VERSION 5.8 ;
BUSBITCHARS "[]" ;
DIVIDERCHAR "/" ;
UNITS
    DATABASE MICRONS 1000 ;
END UNITS

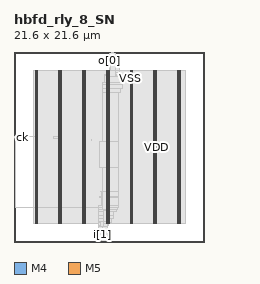
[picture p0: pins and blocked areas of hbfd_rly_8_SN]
MACRO hbfd_rly_8_SN
  FOREIGN hbfd_rly_8_SN 0 0 ;
  CLASS BLOCK ;
  SIZE 21.6 BY 21.6 ;
  PIN ck
    DIRECTION INPUT ;
    USE SIGNAL ;
    PORT
      LAYER M4 ;
        RECT  0 11.856 0.084 11.88 ;
    END
  END ck
  PIN i[0]
    DIRECTION INPUT ;
    USE SIGNAL ;
    PORT
      LAYER M5 ;
        RECT  9.936 0 9.96 0.084 ;
    END
  END i[0]
  PIN i[1]
    DIRECTION INPUT ;
    USE SIGNAL ;
    PORT
      LAYER M5 ;
        RECT  10.032 0 10.056 0.084 ;
    END
  END i[1]
  PIN i[2]
    DIRECTION INPUT ;
    USE SIGNAL ;
    PORT
      LAYER M5 ;
        RECT  10.128 0 10.152 0.084 ;
    END
  END i[2]
  PIN i[3]
    DIRECTION INPUT ;
    USE SIGNAL ;
    PORT
      LAYER M5 ;
        RECT  10.224 0 10.248 0.084 ;
    END
  END i[3]
  PIN i[4]
    DIRECTION INPUT ;
    USE SIGNAL ;
    PORT
      LAYER M5 ;
        RECT  10.32 0 10.344 0.084 ;
    END
  END i[4]
  PIN i[5]
    DIRECTION INPUT ;
    USE SIGNAL ;
    PORT
      LAYER M5 ;
        RECT  10.416 0 10.44 0.084 ;
    END
  END i[5]
  PIN i[6]
    DIRECTION INPUT ;
    USE SIGNAL ;
    PORT
      LAYER M5 ;
        RECT  10.512 0 10.536 0.084 ;
    END
  END i[6]
  PIN i[7]
    DIRECTION INPUT ;
    USE SIGNAL ;
    PORT
      LAYER M5 ;
        RECT  10.608 0 10.632 0.084 ;
    END
  END i[7]
  PIN o[0]
    DIRECTION OUTPUT ;
    USE SIGNAL ;
    PORT
      LAYER M5 ;
        RECT  10.896 21.516 10.92 21.6 ;
    END
  END o[0]
  PIN o[1]
    DIRECTION OUTPUT ;
    USE SIGNAL ;
    PORT
      LAYER M5 ;
        RECT  10.992 21.516 11.016 21.6 ;
    END
  END o[1]
  PIN o[2]
    DIRECTION OUTPUT ;
    USE SIGNAL ;
    PORT
      LAYER M5 ;
        RECT  11.088 21.516 11.112 21.6 ;
    END
  END o[2]
  PIN o[3]
    DIRECTION OUTPUT ;
    USE SIGNAL ;
    PORT
      LAYER M5 ;
        RECT  11.184 21.516 11.208 21.6 ;
    END
  END o[3]
  PIN o[4]
    DIRECTION OUTPUT ;
    USE SIGNAL ;
    PORT
      LAYER M5 ;
        RECT  11.28 21.516 11.304 21.6 ;
    END
  END o[4]
  PIN o[5]
    DIRECTION OUTPUT ;
    USE SIGNAL ;
    PORT
      LAYER M5 ;
        RECT  11.376 21.516 11.4 21.6 ;
    END
  END o[5]
  PIN o[6]
    DIRECTION OUTPUT ;
    USE SIGNAL ;
    PORT
      LAYER M5 ;
        RECT  11.472 21.516 11.496 21.6 ;
    END
  END o[6]
  PIN o[7]
    DIRECTION OUTPUT ;
    USE SIGNAL ;
    PORT
      LAYER M5 ;
        RECT  11.568 21.516 11.592 21.6 ;
    END
  END o[7]
  PIN rs
    DIRECTION INPUT ;
    USE SIGNAL ;
    PORT
      LAYER M4 ;
        RECT  0 11.952 0.084 11.976 ;
    END
  END rs
  PIN VDD
    DIRECTION INOUT ;
    USE POWER ;
    PORT
      LAYER M5 ;
        RECT  18.792 2.151 18.912 19.449 ;
        RECT  16.092 2.151 16.212 19.449 ;
        RECT  13.392 2.151 13.512 19.449 ;
        RECT  10.692 2.151 10.812 19.449 ;
        RECT  7.992 2.151 8.112 19.449 ;
        RECT  5.292 2.151 5.412 19.449 ;
        RECT  2.592 2.151 2.712 19.449 ;
    END
  END VDD
  PIN VSS
    DIRECTION INOUT ;
    USE GROUND ;
    PORT
      LAYER M5 ;
        RECT  18.6 2.137 18.72 19.463 ;
        RECT  15.9 2.137 16.02 19.463 ;
        RECT  13.2 2.137 13.32 19.463 ;
        RECT  10.5 2.137 10.62 19.463 ;
        RECT  7.8 2.137 7.92 19.463 ;
        RECT  5.1 2.137 5.22 19.463 ;
        RECT  2.4 2.137 2.52 19.463 ;
    END
  END VSS
  # OT_OBS_CLOSED layer=M5 d_um=1.536 added=3
  OBS
    LAYER RVTN ;
     RECT  2.16 2.16 19.44 2.295 ;
     RECT  2.16 2.565 19.44 2.835 ;
     RECT  2.16 3.105 19.44 3.375 ;
     RECT  2.16 3.645 19.44 3.915 ;
     RECT  2.16 4.185 19.44 4.455 ;
     RECT  2.16 4.725 19.44 4.995 ;
     RECT  2.16 5.265 19.44 5.535 ;
     RECT  2.16 5.805 19.44 6.075 ;
     RECT  2.16 6.345 19.44 6.615 ;
     RECT  2.16 6.885 19.44 7.155 ;
     RECT  2.16 7.425 19.44 7.695 ;
     RECT  2.16 7.965 19.44 8.235 ;
     RECT  2.16 8.505 19.44 8.775 ;
     RECT  2.16 9.045 19.44 9.315 ;
     RECT  2.16 9.585 19.44 9.855 ;
     RECT  2.16 10.125 19.44 10.395 ;
     RECT  2.16 10.665 19.44 10.935 ;
     RECT  2.16 11.205 19.44 11.475 ;
     RECT  2.16 11.745 19.44 12.015 ;
     RECT  2.16 12.285 19.44 12.555 ;
     RECT  2.16 12.825 19.44 13.095 ;
     RECT  2.16 13.365 19.44 13.635 ;
     RECT  2.16 13.905 19.44 14.175 ;
     RECT  2.16 14.445 19.44 14.715 ;
     RECT  2.16 14.985 19.44 15.255 ;
     RECT  2.16 15.525 19.44 15.795 ;
     RECT  2.16 16.065 19.44 16.335 ;
     RECT  2.16 16.605 19.44 16.875 ;
     RECT  2.16 17.145 19.44 17.415 ;
     RECT  2.16 17.685 19.44 17.955 ;
     RECT  2.16 18.225 19.44 18.495 ;
     RECT  2.16 18.765 19.44 19.035 ;
     RECT  2.16 19.305 19.44 19.44 ;
    LAYER RVTP ;
     RECT  2.16 2.295 19.44 2.565 ;
     RECT  2.16 2.835 19.44 3.105 ;
     RECT  2.16 3.375 19.44 3.645 ;
     RECT  2.16 3.915 19.44 4.185 ;
     RECT  2.16 4.455 19.44 4.725 ;
     RECT  2.16 4.995 19.44 5.265 ;
     RECT  2.16 5.535 19.44 5.805 ;
     RECT  2.16 6.075 19.44 6.345 ;
     RECT  2.16 6.615 19.44 6.885 ;
     RECT  2.16 7.155 19.44 7.425 ;
     RECT  2.16 7.695 19.44 7.965 ;
     RECT  2.16 8.235 19.44 8.505 ;
     RECT  2.16 8.775 19.44 9.045 ;
     RECT  2.16 9.315 19.44 9.585 ;
     RECT  2.16 9.855 19.44 10.125 ;
     RECT  2.16 10.395 19.44 10.665 ;
     RECT  2.16 10.935 19.44 11.205 ;
     RECT  2.16 11.475 19.44 11.745 ;
     RECT  2.16 12.015 19.44 12.285 ;
     RECT  2.16 12.555 19.44 12.825 ;
     RECT  2.16 13.095 19.44 13.365 ;
     RECT  2.16 13.635 19.44 13.905 ;
     RECT  2.16 14.175 19.44 14.445 ;
     RECT  2.16 14.715 19.44 14.985 ;
     RECT  2.16 15.255 19.44 15.525 ;
     RECT  2.16 15.795 19.44 16.065 ;
     RECT  2.16 16.335 19.44 16.605 ;
     RECT  2.16 16.875 19.44 17.145 ;
     RECT  2.16 17.415 19.44 17.685 ;
     RECT  2.16 17.955 19.44 18.225 ;
     RECT  2.16 18.495 19.44 18.765 ;
     RECT  2.16 19.035 19.44 19.305 ;
    LAYER M1 ;
     RECT  2.16 2.151 19.44 19.449 ;
    LAYER M2 ;
     RECT  2.16 2.151 19.44 19.449 ;
    LAYER M3 ;
     RECT  10.188 0.091 10.206 0.571 ;
     RECT  9.576 0.571 10.206 1.723 ;
     RECT  9.576 1.723 10.674 1.819 ;
     RECT  9.576 1.819 10.71 2.191 ;
     RECT  2.415 2.143 2.505 2.413 ;
     RECT  5.115 2.143 5.205 2.413 ;
     RECT  7.815 2.143 7.905 2.413 ;
     RECT  13.215 2.143 13.305 2.413 ;
     RECT  15.915 2.143 16.005 2.413 ;
     RECT  18.615 2.143 18.705 2.413 ;
     RECT  9.576 2.191 11.106 2.641 ;
     RECT  9.576 2.641 11.358 3.065 ;
     RECT  9.612 3.065 11.358 3.451 ;
     RECT  9.612 3.451 11.682 3.721 ;
     RECT  9.612 3.721 11.718 3.953 ;
     RECT  9.612 3.953 11.826 4.145 ;
     RECT  9.972 4.145 11.826 5.035 ;
     RECT  9.684 5.035 11.826 5.071 ;
     RECT  9.684 5.071 11.898 5.225 ;
     RECT  9.9 5.225 11.898 5.765 ;
     RECT  10.008 5.765 11.898 8.509 ;
     RECT  9.684 8.509 11.898 11.399 ;
     RECT  8.82 11.515 8.838 11.669 ;
     RECT  5.115 2.413 5.397 11.785 ;
     RECT  4.464 11.785 5.397 11.939 ;
     RECT  2.415 2.413 2.697 11.941 ;
     RECT  2.304 11.941 2.697 11.981 ;
     RECT  10.044 11.399 11.898 17.041 ;
     RECT  10.044 17.041 12.114 17.491 ;
     RECT  10.044 17.491 12.294 17.915 ;
     RECT  10.044 17.915 12.222 18.149 ;
     RECT  10.26 18.149 12.222 18.959 ;
     RECT  10.26 18.959 12.114 18.995 ;
     RECT  2.415 11.981 2.697 19.187 ;
     RECT  5.115 11.939 5.397 19.187 ;
     RECT  7.815 2.413 8.097 19.187 ;
     RECT  13.215 2.413 13.497 19.187 ;
     RECT  15.915 2.413 16.197 19.187 ;
     RECT  18.615 2.413 18.897 19.187 ;
     RECT  10.515 18.995 12.114 19.229 ;
     RECT  10.515 19.229 12.042 19.265 ;
     RECT  2.415 19.187 2.505 19.457 ;
     RECT  5.115 19.187 5.205 19.457 ;
     RECT  7.815 19.187 7.905 19.457 ;
     RECT  10.515 19.265 11.97 19.457 ;
     RECT  13.215 19.187 13.305 19.457 ;
     RECT  15.915 19.187 16.005 19.457 ;
     RECT  18.615 19.187 18.705 19.457 ;
     RECT  10.872 19.457 11.97 19.949 ;
     RECT  10.872 19.949 11.178 19.997 ;
     RECT  11.16 19.997 11.178 20.525 ;
     RECT  11.952 19.949 11.97 20.525 ;
    LAYER M4 ;
     RECT  0.06 11.856 0.227 11.976 ;
     RECT  0.181 3.888 2.408 3.912 ;
     RECT  0.227 11.952 2.408 11.976 ;
     RECT  2.408 2.148 2.512 19.452 ;
     RECT  2.512 2.418 2.704 19.182 ;
     RECT  2.704 3.888 5.108 3.912 ;
     RECT  5.108 2.148 5.212 19.452 ;
     RECT  5.212 2.418 5.404 19.182 ;
     RECT  5.404 3.888 7.808 3.912 ;
     RECT  7.808 2.148 7.912 19.452 ;
     RECT  7.912 2.418 8.104 19.182 ;
     RECT  9.601 2.256 9.853 2.28 ;
     RECT  9.565 0.576 9.971 0.6 ;
     RECT  8.104 3.888 10.028 3.912 ;
     RECT  10.028 3.696 10.316 3.912 ;
     RECT  10.316 3.6 10.357 3.912 ;
     RECT  10.177 0.096 10.451 0.12 ;
     RECT  9.853 1.728 10.508 2.28 ;
     RECT  10.357 3.6 10.508 3.96 ;
     RECT  9.889 5.712 10.508 5.736 ;
     RECT  10.508 1.728 10.685 19.452 ;
     RECT  10.685 1.824 10.721 19.452 ;
     RECT  10.721 2.418 10.804 19.452 ;
     RECT  10.804 18.816 10.861 19.452 ;
     RECT  10.861 18.816 10.885 19.992 ;
     RECT  10.885 18.816 11.297 20.52 ;
     RECT  11.297 18.816 11.411 19.368 ;
     RECT  11.411 18.816 11.981 18.84 ;
     RECT  11.297 20.496 11.981 20.52 ;
     RECT  13.208 2.148 13.312 19.452 ;
     RECT  13.312 2.418 13.504 19.182 ;
     RECT  15.908 2.148 16.012 19.452 ;
     RECT  16.012 2.418 16.204 19.182 ;
     RECT  18.608 2.148 18.712 19.452 ;
     RECT  18.712 2.418 18.904 19.182 ;
    LAYER M5 ;
     RECT  9.936 0.016 10.632 0.611 ;
     RECT  10.032 0.611 10.632 1.763 ;
     RECT  2.4 2.137 2.52 2.151 ;
     RECT  5.1 2.137 5.22 2.151 ;
     RECT  7.8 2.137 7.92 2.151 ;
     RECT  10.128 1.763 10.632 2.151 ;
     RECT  13.2 2.137 13.32 2.151 ;
     RECT  15.9 2.137 16.02 2.151 ;
     RECT  18.6 2.137 18.72 2.151 ;
     RECT  10.128 2.151 10.812 2.291 ;
     RECT  10.5 2.291 10.812 3.589 ;
     RECT  10.368 3.589 10.812 3.685 ;
     RECT  10.08 3.685 10.812 5.747 ;
     RECT  0.192 3.877 0.216 11.891 ;
     RECT  10.5 5.747 10.812 18.805 ;
     RECT  2.4 2.151 2.712 19.449 ;
     RECT  5.1 2.151 5.412 19.449 ;
     RECT  7.8 2.151 8.112 19.449 ;
     RECT  13.2 2.151 13.512 19.449 ;
     RECT  15.9 2.151 16.212 19.449 ;
     RECT  18.6 2.151 18.912 19.449 ;
     RECT  2.4 19.449 2.52 19.463 ;
     RECT  5.1 19.449 5.22 19.463 ;
     RECT  7.8 19.449 7.92 19.463 ;
     RECT  10.5 18.805 11.496 19.463 ;
     RECT  13.2 19.449 13.32 19.463 ;
     RECT  15.9 19.449 16.02 19.463 ;
     RECT  18.6 19.449 18.72 19.463 ;
     RECT  10.992 19.463 11.496 20.485 ;
     RECT  10.896 20.485 11.592 21.584 ;
     RECT  10.128 2.291 10.5 3.589 ;
     RECT  10.128 3.589 10.368 3.685 ;
     RECT  10.896 19.463 10.992 20.485 ;
  END
END hbfd_rly_8_SN
END LIBRARY
